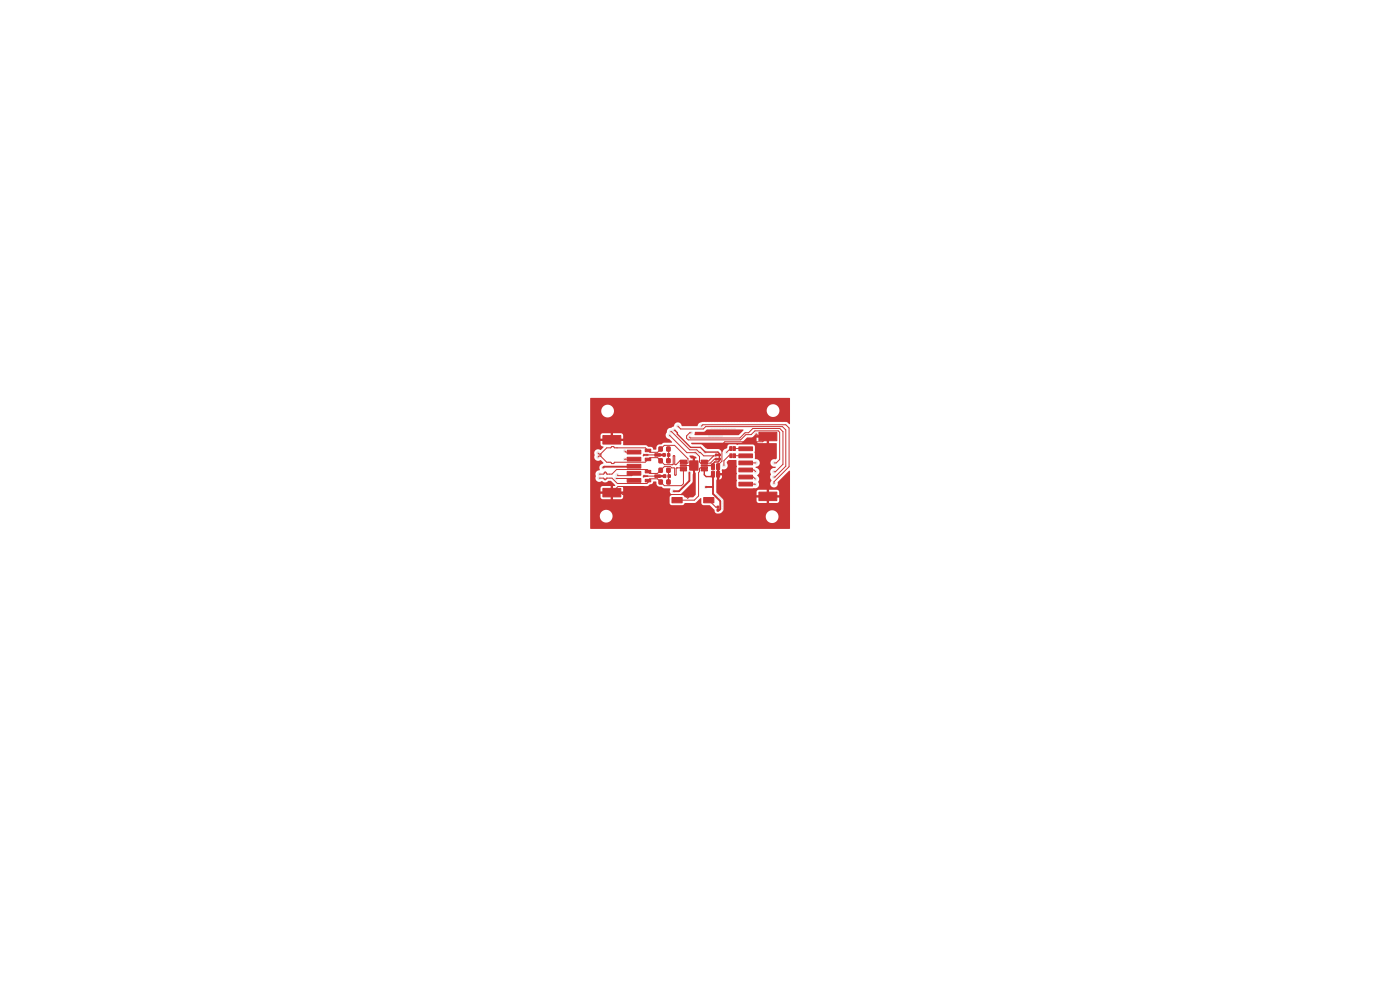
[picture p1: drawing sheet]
<svg xmlns="http://www.w3.org/2000/svg" width="297mm" height="210mm" viewBox="0 0 297 210" stroke-linecap="round" stroke-linejoin="round" font-family="sans-serif">
<g fill="#c83434" stroke="#c83434" stroke-width=".21">
<path d="M136.9 95.3h1.2v.5h-1.2z"/>
<path d="M136.9 97.2h1.2v.5h-1.2z"/>
<path d="M138.9 96.2h1.2v.6h-1.2z"/>
<path d="M155.5 96.3h.5v.8h-.5z"/>
<path d="M154.8 96.3h.5v.8h-.5z"/>
<path d="M139.8 97.3h.7v.9h-.7z"/>
<path d="M141.5 97.3h.6v.9h-.6z"/>
<path d="M141.7 100.7h.5v.6h-.5z"/>
<path d="M140.8 100.7h.4v.6h-.4z"/>
<path d="M139.8 94.8h.7v.9h-.7z"/>
<path d="M141.5 94.8h.6v.9h-.6z"/>
<path d="M152.4 97.2h.4v.4h-.4z"/>
<path d="M151.8 97.2h.4v.4h-.4z"/>
<path d="M151.8 96.3h.4v.4h-.4z"/>
<path d="M152.4 96.3h.4v.4h-.4z"/>
<path d="M149.3 105.5h2.1v1.2h-2.1z"/>
<path d="M142.6 105.5h2.1v1.2h-2.1z"/>
<path d="M144.3 97.6h1.4v.3h-1.4z"/>
<path d="M144.3 98.1h1.4v.3h-1.4z"/>
<path d="M144.3 98.6h1.4v.3h-1.4z"/>
<path d="M144.3 99.1h1.4v.3h-1.4z"/>
<path d="M144.3 99.6h1.4v.3h-1.4z"/>
<path d="M148.7 99.6h1.4v.3h-1.4z"/>
<path d="M148.7 99.1h1.4v.3h-1.4z"/>
<path d="M148.7 98.6h1.4v.3h-1.4z"/>
<path d="M148.7 98.1h1.4v.3h-1.4z"/>
<path d="M148.7 97.6h1.4v.3h-1.4z"/>
<path d="M146.3 97.8h1.8v1.9h-1.8z"/>
<path d="M152.1 107.4h.4v.4h-.4z"/>
<path d="M152.1 108h.4v.4h-.4z"/>
<path d="M136.9 99.8h1.2v.5h-1.2z"/>
<path d="M136.9 101.7h1.2v.5h-1.2z"/>
<path d="M138.9 100.7h1.2v.6h-1.2z"/>
<path d="M151 100l.6 .1-.1 1.1-.6-.1z"/>
<path d="M152.1 100l.6 .1-.1 1.1-.6-.1z"/>
<path d="M156.8 102.3h2.8v.8h-2.8z"/>
<path d="M156.8 100.8h2.8v.8h-2.8z"/>
<path d="M156.8 99.3h2.8v.8h-2.8z"/>
<path d="M156.8 97.8h2.8v.8h-2.8z"/>
<path d="M156.8 96.3h2.8v.8h-2.8z"/>
<path d="M156.8 94.8h2.8v.8h-2.8z"/>
<path d="M161 104.4h3.8v1.8h-3.8z"/>
<path d="M161 91.7h3.8v1.8h-3.8z"/>
<path d="M141.5 101.8h.7v.9h-.7z"/>
<path d="M139.8 101.8h.7v.9h-.7z"/>
<path d="M139.8 99.3h.7v.9h-.7z"/>
<path d="M141.5 99.3h.7v.9h-.7z"/>
<path d="M141.6 96.2h.5v.6h-.5z"/>
<path d="M140.7 96.2h.4v.6h-.4z"/>
<path d="M151 98.4l.6 .1-.1 1.1-.6-.1z"/>
<path d="M152.1 98.4l.6 .1-.1 1.1-.6-.1z"/>
<path d="M155.5 94.7h.5v.8h-.5z"/>
<path d="M154.8 94.7h.5v.8h-.5z"/>
<path d="M133.1 95.5h2.8v.8h-2.8z"/>
<path d="M133.1 97h2.8v.8h-2.8z"/>
<path d="M133.1 98.5h2.8v.8h-2.8z"/>
<path d="M133.1 100h2.8v.8h-2.8z"/>
<path d="M133.1 101.5h2.8v.8h-2.8z"/>
<path d="M127.9 92.4h3.8v1.8h-3.8z"/>
<path d="M127.9 103.6h3.8v1.8h-3.8z"/>
</g>
<g fill="#ececec" stroke="#ececec" stroke-width=".21">
<circle cx="143" cy="91.3" r=".3"/>
<circle cx="149.6" cy="95.9" r=".3"/>
<circle cx="137.2" cy="85" r=".3"/>
<circle cx="152.3" cy="103.2" r=".3"/>
<circle cx="139.2" cy="106.2" r=".3"/>
<circle cx="132" cy="109.2" r=".3"/>
<circle cx="141.4" cy="88.6" r=".3"/>
<circle cx="138.4" cy="86.2" r=".3"/>
<circle cx="151.6" cy="91.2" r=".3"/>
<circle cx="154.6" cy="87.4" r=".3"/>
<circle cx="159" cy="111.6" r=".3"/>
<circle cx="161.4" cy="108" r=".3"/>
<circle cx="160" cy="89.2" r=".3"/>
<circle cx="159.4" cy="89.2" r=".3"/>
<circle cx="127" cy="90.4" r=".3"/>
<circle cx="143.8" cy="86.2" r=".3"/>
<circle cx="138.6" cy="108" r=".3"/>
<circle cx="148.8" cy="110.4" r=".3"/>
<circle cx="137.2" cy="86.8" r=".3"/>
<circle cx="138.4" cy="88" r=".3"/>
<circle cx="126.4" cy="85" r=".3"/>
<circle cx="149.8" cy="85.6" r=".3"/>
<circle cx="139.8" cy="105.6" r=".3"/>
<circle cx="154.7" cy="103.2" r=".3"/>
<circle cx="134.4" cy="109.2" r=".3"/>
<circle cx="140.8" cy="89.2" r=".3"/>
<circle cx="155.8" cy="85" r=".3"/>
<circle cx="154.6" cy="89.2" r=".3"/>
<circle cx="151" cy="86.8" r=".3"/>
<circle cx="149.8" cy="88.6" r=".3"/>
<circle cx="139" cy="85" r=".3"/>
<circle cx="136.2" cy="110.4" r=".3"/>
<circle cx="161.2" cy="85" r=".3"/>
<circle cx="143.2" cy="86.2" r=".3"/>
<circle cx="129.6" cy="106.8" r=".3"/>
<circle cx="151.6" cy="88" r=".3"/>
<circle cx="141.6" cy="107.4" r=".3"/>
<circle cx="144.4" cy="88.6" r=".3"/>
<circle cx="133.8" cy="106.8" r=".3"/>
<circle cx="133.2" cy="109.8" r=".3"/>
<circle cx="127.6" cy="90.4" r=".3"/>
<circle cx="136.8" cy="111" r=".3"/>
<circle cx="140.2" cy="89.2" r=".3"/>
<circle cx="131.8" cy="86.2" r=".3"/>
<circle cx="134.8" cy="85" r=".3"/>
<circle cx="135" cy="107.4" r=".3"/>
<circle cx="159.6" cy="107.4" r=".3"/>
<circle cx="151" cy="87.4" r=".3"/>
<circle cx="135.4" cy="85" r=".3"/>
<circle cx="132.4" cy="88.6" r=".3"/>
<circle cx="156.4" cy="85" r=".3"/>
<circle cx="125.8" cy="85.6" r=".3"/>
<circle cx="136" cy="86.2" r=".3"/>
<circle cx="146.8" cy="85.6" r=".3"/>
<circle cx="166.7" cy="85" r=".3"/>
<circle cx="154" cy="85.6" r=".3"/>
<circle cx="156.4" cy="85.6" r=".3"/>
<circle cx="141.4" cy="86.8" r=".3"/>
<circle cx="134.8" cy="89.2" r=".3"/>
<circle cx="136" cy="88.6" r=".3"/>
<circle cx="156.4" cy="88" r=".3"/>
<circle cx="152.8" cy="91.2" r=".3"/>
<circle cx="145.8" cy="111" r=".3"/>
<circle cx="138.4" cy="89.2" r=".3"/>
<circle cx="152.4" cy="111" r=".3"/>
<circle cx="160.6" cy="86.8" r=".3"/>
<circle cx="149.2" cy="88.6" r=".3"/>
<circle cx="152.8" cy="87.4" r=".3"/>
<circle cx="137.8" cy="89.2" r=".3"/>
<circle cx="136.8" cy="109.8" r=".3"/>
<circle cx="146.4" cy="109.8" r=".3"/>
<circle cx="154.2" cy="111" r=".3"/>
<circle cx="155.4" cy="106.8" r=".3"/>
<circle cx="157" cy="86.2" r=".3"/>
<circle cx="149.2" cy="88" r=".3"/>
<circle cx="131.8" cy="86.8" r=".3"/>
<circle cx="153.5" cy="104.4" r=".3"/>
<circle cx="159" cy="110.4" r=".3"/>
<circle cx="145.6" cy="86.2" r=".3"/>
<circle cx="132.4" cy="85" r=".3"/>
<circle cx="132" cy="108" r=".3"/>
<circle cx="153.6" cy="106.2" r=".3"/>
<circle cx="136.8" cy="108.6" r=".3"/>
<circle cx="151.8" cy="109.2" r=".3"/>
<circle cx="151.6" cy="85" r=".3"/>
<circle cx="138" cy="107.4" r=".3"/>
<circle cx="137.4" cy="109.2" r=".3"/>
<circle cx="138" cy="108" r=".3"/>
<circle cx="158.2" cy="86.2" r=".3"/>
<circle cx="143.2" cy="89.2" r=".3"/>
<circle cx="154.8" cy="111.6" r=".3"/>
<circle cx="158.4" cy="108.6" r=".3"/>
<circle cx="149.8" cy="85" r=".3"/>
<circle cx="155.8" cy="91.2" r=".3"/>
<circle cx="154.8" cy="109.8" r=".3"/>
<circle cx="157.6" cy="89.2" r=".3"/>
<circle cx="133.6" cy="88.6" r=".3"/>
<circle cx="153.5" cy="102.6" r=".3"/>
<circle cx="156.6" cy="109.2" r=".3"/>
<circle cx="139.2" cy="106.8" r=".3"/>
<circle cx="133" cy="90.4" r=".3"/>
<circle cx="155.3" cy="104.4" r=".3"/>
<circle cx="151.2" cy="111" r=".3"/>
<circle cx="160.2" cy="109.2" r=".3"/>
<circle cx="125.8" cy="88" r=".3"/>
<circle cx="136" cy="89.8" r=".3"/>
<circle cx="137.4" cy="107.4" r=".3"/>
<circle cx="158.2" cy="86.8" r=".3"/>
<circle cx="150.4" cy="86.2" r=".3"/>
<circle cx="142.8" cy="109.2" r=".3"/>
<circle cx="137.8" cy="87.4" r=".3"/>
<circle cx="136" cy="87.4" r=".3"/>
<circle cx="160" cy="87.4" r=".3"/>
<circle cx="159.4" cy="85.6" r=".3"/>
<circle cx="152.9" cy="102.6" r=".3"/>
<circle cx="142" cy="87.4" r=".3"/>
<circle cx="142.6" cy="88" r=".3"/>
<circle cx="155.2" cy="91.2" r=".3"/>
<circle cx="160.2" cy="111.6" r=".3"/>
<circle cx="160.4" cy="92" r=".3"/>
<circle cx="143.2" cy="88.6" r=".3"/>
<circle cx="135.4" cy="90.4" r=".3"/>
<circle cx="152.2" cy="89.2" r=".3"/>
<circle cx="166.7" cy="88.6" r=".3"/>
<circle cx="159" cy="109.2" r=".3"/>
<circle cx="139" cy="87.4" r=".3"/>
<circle cx="147.6" cy="111" r=".3"/>
<circle cx="135" cy="109.2" r=".3"/>
<circle cx="145.6" cy="87.4" r=".3"/>
<circle cx="150.4" cy="87.4" r=".3"/>
<circle cx="165.8" cy="107.4" r=".3"/>
<circle cx="154" cy="86.2" r=".3"/>
<circle cx="157" cy="85" r=".3"/>
<circle cx="157.2" cy="109.8" r=".3"/>
<circle cx="143.2" cy="87.4" r=".3"/>
<circle cx="140.2" cy="88.6" r=".3"/>
<circle cx="152.9" cy="103.2" r=".3"/>
<circle cx="159.6" cy="110.4" r=".3"/>
<circle cx="166.7" cy="86.2" r=".3"/>
<circle cx="154" cy="85" r=".3"/>
<circle cx="143.2" cy="85" r=".3"/>
<circle cx="151.6" cy="89.2" r=".3"/>
<circle cx="139.8" cy="109.2" r=".3"/>
<circle cx="148.8" cy="111.6" r=".3"/>
<circle cx="157" cy="88" r=".3"/>
<circle cx="133.2" cy="111" r=".3"/>
<circle cx="156" cy="109.2" r=".3"/>
<circle cx="137.4" cy="106.2" r=".3"/>
<circle cx="160.6" cy="88.6" r=".3"/>
<circle cx="125.8" cy="89.2" r=".3"/>
<circle cx="145.8" cy="110.4" r=".3"/>
<circle cx="154.8" cy="108.6" r=".3"/>
<circle cx="151.8" cy="111.6" r=".3"/>
<circle cx="136" cy="85" r=".3"/>
<circle cx="134.2" cy="85" r=".3"/>
<circle cx="158.8" cy="85.6" r=".3"/>
<circle cx="155.1" cy="101.2" r=".3"/>
<circle cx="157.8" cy="108" r=".3"/>
<circle cx="138.4" cy="85" r=".3"/>
<circle cx="137.8" cy="86.2" r=".3"/>
<circle cx="132" cy="108.6" r=".3"/>
<circle cx="152.9" cy="105" r=".3"/>
<circle cx="143.4" cy="110.4" r=".3"/>
<circle cx="153.6" cy="109.2" r=".3"/>
<circle cx="154" cy="88" r=".3"/>
<circle cx="167" cy="108" r=".3"/>
<circle cx="150.4" cy="88" r=".3"/>
<circle cx="153.6" cy="106.8" r=".3"/>
<circle cx="139.6" cy="85.6" r=".3"/>
<circle cx="132" cy="111" r=".3"/>
<circle cx="142.6" cy="88.6" r=".3"/>
<circle cx="145.6" cy="85" r=".3"/>
<circle cx="136.6" cy="85.6" r=".3"/>
<circle cx="148" cy="87.4" r=".3"/>
<circle cx="155.2" cy="85.6" r=".3"/>
<circle cx="133" cy="85" r=".3"/>
<circle cx="146.2" cy="85.6" r=".3"/>
<circle cx="126.4" cy="90.4" r=".3"/>
<circle cx="141.4" cy="85.6" r=".3"/>
<circle cx="166.1" cy="85" r=".3"/>
<circle cx="160" cy="88.6" r=".3"/>
<circle cx="161.8" cy="85" r=".3"/>
<circle cx="137.8" cy="88.6" r=".3"/>
<circle cx="135.6" cy="111.6" r=".3"/>
<circle cx="126" cy="106.8" r=".3"/>
<circle cx="152.8" cy="85.6" r=".3"/>
<circle cx="145" cy="86.2" r=".3"/>
<circle cx="155.4" cy="111" r=".3"/>
<circle cx="156" cy="107.4" r=".3"/>
<circle cx="145" cy="88" r=".3"/>
<circle cx="132" cy="106.8" r=".3"/>
<circle cx="141.6" cy="111.6" r=".3"/>
<circle cx="152.2" cy="87.4" r=".3"/>
<circle cx="153.5" cy="105.6" r=".3"/>
<circle cx="137.4" cy="111" r=".3"/>
<circle cx="144.4" cy="88" r=".3"/>
<circle cx="138" cy="111.6" r=".3"/>
<circle cx="154.2" cy="106.8" r=".3"/>
<circle cx="142.8" cy="110.4" r=".3"/>
<circle cx="145" cy="87.4" r=".3"/>
<circle cx="142.6" cy="85" r=".3"/>
<circle cx="160.8" cy="109.2" r=".3"/>
<circle cx="157" cy="86.8" r=".3"/>
<circle cx="144.6" cy="111" r=".3"/>
<circle cx="138.4" cy="85.6" r=".3"/>
<circle cx="140.4" cy="109.2" r=".3"/>
<circle cx="139" cy="88" r=".3"/>
<circle cx="136.6" cy="85" r=".3"/>
<circle cx="149.2" cy="86.8" r=".3"/>
<circle cx="159" cy="109.8" r=".3"/>
<circle cx="155.4" cy="110.4" r=".3"/>
<circle cx="132.4" cy="86.8" r=".3"/>
<circle cx="141" cy="109.2" r=".3"/>
<circle cx="157.6" cy="85.6" r=".3"/>
<circle cx="159.6" cy="108" r=".3"/>
<circle cx="131.8" cy="88" r=".3"/>
<circle cx="132.6" cy="109.2" r=".3"/>
<circle cx="157.8" cy="109.8" r=".3"/>
<circle cx="143.8" cy="88.6" r=".3"/>
<circle cx="130.8" cy="106.8" r=".3"/>
<circle cx="156.6" cy="109.8" r=".3"/>
<circle cx="143.4" cy="109.8" r=".3"/>
<circle cx="136.6" cy="89.2" r=".3"/>
<circle cx="131.8" cy="85.6" r=".3"/>
<circle cx="138.6" cy="107.4" r=".3"/>
<circle cx="139.6" cy="86.8" r=".3"/>
<circle cx="148.2" cy="111" r=".3"/>
<circle cx="141.6" cy="106.2" r=".3"/>
<circle cx="153" cy="111.6" r=".3"/>
<circle cx="136" cy="88" r=".3"/>
<circle cx="132.4" cy="87.4" r=".3"/>
<circle cx="130.6" cy="89.8" r=".3"/>
<circle cx="147" cy="109.8" r=".3"/>
<circle cx="152.4" cy="110.4" r=".3"/>
<circle cx="136.8" cy="107.4" r=".3"/>
<circle cx="158.4" cy="109.2" r=".3"/>
<circle cx="154.2" cy="108" r=".3"/>
<circle cx="127" cy="85" r=".3"/>
<circle cx="153" cy="109.8" r=".3"/>
<circle cx="157.2" cy="110.4" r=".3"/>
<circle cx="159" cy="108.6" r=".3"/>
<circle cx="137.2" cy="96.5" r=".3"/>
<circle cx="154" cy="89.2" r=".3"/>
<circle cx="127.6" cy="91" r=".3"/>
<circle cx="139" cy="88.6" r=".3"/>
<circle cx="132.6" cy="108.6" r=".3"/>
<circle cx="135.6" cy="107.4" r=".3"/>
<circle cx="150.6" cy="110.4" r=".3"/>
<circle cx="144" cy="111" r=".3"/>
<circle cx="136.8" cy="106.2" r=".3"/>
<circle cx="166.4" cy="111.6" r=".3"/>
<circle cx="160.6" cy="86.2" r=".3"/>
<circle cx="156.4" cy="88.6" r=".3"/>
<circle cx="148.6" cy="89.2" r=".3"/>
<circle cx="125.8" cy="87.4" r=".3"/>
<circle cx="146.8" cy="88" r=".3"/>
<circle cx="154.8" cy="106.2" r=".3"/>
<circle cx="150.6" cy="109.8" r=".3"/>
<circle cx="158.8" cy="89.2" r=".3"/>
<circle cx="152.8" cy="88" r=".3"/>
<circle cx="135.4" cy="89.2" r=".3"/>
<circle cx="131.2" cy="85" r=".3"/>
<circle cx="157.2" cy="108.6" r=".3"/>
<circle cx="136.2" cy="106.8" r=".3"/>
<circle cx="157.6" cy="85" r=".3"/>
<circle cx="155.2" cy="87.4" r=".3"/>
<circle cx="159.4" cy="86.8" r=".3"/>
<circle cx="156" cy="109.8" r=".3"/>
<circle cx="155.3" cy="105.6" r=".3"/>
<circle cx="153.6" cy="110.4" r=".3"/>
<circle cx="155.7" cy="101.2" r=".3"/>
<circle cx="154.7" cy="105" r=".3"/>
<circle cx="126" cy="111" r=".3"/>
<circle cx="148.6" cy="86.2" r=".3"/>
<circle cx="167" cy="111.6" r=".3"/>
<circle cx="131.2" cy="90.4" r=".3"/>
<circle cx="145.2" cy="109.8" r=".3"/>
<circle cx="138.6" cy="109.2" r=".3"/>
<circle cx="137.2" cy="89.2" r=".3"/>
<circle cx="150.6" cy="111" r=".3"/>
<circle cx="136.2" cy="109.8" r=".3"/>
<circle cx="157.6" cy="88.6" r=".3"/>
<circle cx="128.2" cy="91" r=".3"/>
<circle cx="166.4" cy="108" r=".3"/>
<circle cx="151.2" cy="110.4" r=".3"/>
<circle cx="138.6" cy="111" r=".3"/>
<circle cx="135" cy="108" r=".3"/>
<circle cx="136.8" cy="106.8" r=".3"/>
<circle cx="155.4" cy="108.6" r=".3"/>
<circle cx="151.6" cy="85.6" r=".3"/>
<circle cx="130.2" cy="106.8" r=".3"/>
<circle cx="136.6" cy="88.6" r=".3"/>
<circle cx="132.4" cy="86.2" r=".3"/>
<circle cx="158.8" cy="86.2" r=".3"/>
<circle cx="146.2" cy="86.2" r=".3"/>
<circle cx="134.8" cy="89.8" r=".3"/>
<circle cx="156.4" cy="86.2" r=".3"/>
<circle cx="157" cy="89.2" r=".3"/>
<circle cx="156.6" cy="108.6" r=".3"/>
<circle cx="153.6" cy="109.8" r=".3"/>
<circle cx="144.4" cy="89.2" r=".3"/>
<circle cx="157.2" cy="111" r=".3"/>
<circle cx="159.6" cy="111" r=".3"/>
<circle cx="145" cy="85" r=".3"/>
<circle cx="148.2" cy="109.8" r=".3"/>
<circle cx="137.2" cy="86.2" r=".3"/>
<circle cx="149.8" cy="86.8" r=".3"/>
<circle cx="129.4" cy="90.4" r=".3"/>
<circle cx="157.8" cy="109.2" r=".3"/>
<circle cx="166.4" cy="107.4" r=".3"/>
<circle cx="139.8" cy="111" r=".3"/>
<circle cx="158.4" cy="111.6" r=".3"/>
<circle cx="160" cy="86.2" r=".3"/>
<circle cx="136.7" cy="101" r=".3"/>
<circle cx="132.4" cy="88" r=".3"/>
<circle cx="131.8" cy="89.2" r=".3"/>
<circle cx="133.6" cy="85" r=".3"/>
<circle cx="145" cy="86.8" r=".3"/>
<circle cx="139.2" cy="110.4" r=".3"/>
<circle cx="152.8" cy="86.2" r=".3"/>
<circle cx="154.2" cy="106.2" r=".3"/>
<circle cx="131.4" cy="108.6" r=".3"/>
<circle cx="126.6" cy="111.6" r=".3"/>
<circle cx="155.2" cy="88" r=".3"/>
<circle cx="152.4" cy="109.8" r=".3"/>
<circle cx="155.8" cy="86.8" r=".3"/>
<circle cx="134.2" cy="85.6" r=".3"/>
<circle cx="133.8" cy="107.4" r=".3"/>
<circle cx="167" cy="109.8" r=".3"/>
<circle cx="151" cy="85.6" r=".3"/>
<circle cx="131.4" cy="111" r=".3"/>
<circle cx="128.2" cy="90.4" r=".3"/>
<circle cx="131.2" cy="91" r=".3"/>
<circle cx="133.2" cy="111.6" r=".3"/>
<circle cx="138.6" cy="111.6" r=".3"/>
<circle cx="131.4" cy="107.4" r=".3"/>
<circle cx="151.6" cy="86.8" r=".3"/>
<circle cx="143.4" cy="109.2" r=".3"/>
<circle cx="134.4" cy="107.4" r=".3"/>
<circle cx="146.8" cy="86.2" r=".3"/>
<circle cx="141.4" cy="87.4" r=".3"/>
<circle cx="154.1" cy="103.8" r=".3"/>
<circle cx="155.8" cy="86.2" r=".3"/>
<circle cx="154.1" cy="105" r=".3"/>
<circle cx="155.7" cy="98.2" r=".3"/>
<circle cx="142" cy="85.6" r=".3"/>
<circle cx="167" cy="111" r=".3"/>
<circle cx="133" cy="85.6" r=".3"/>
<circle cx="155.7" cy="100.6" r=".3"/>
<circle cx="156.4" cy="86.8" r=".3"/>
<circle cx="154.2" cy="110.4" r=".3"/>
<circle cx="134.8" cy="85.6" r=".3"/>
<circle cx="140.4" cy="105.6" r=".3"/>
<circle cx="161.2" cy="87.4" r=".3"/>
<circle cx="146.4" cy="111.6" r=".3"/>
<circle cx="137.8" cy="85" r=".3"/>
<circle cx="155.2" cy="85" r=".3"/>
<circle cx="136.6" cy="86.2" r=".3"/>
<circle cx="160.6" cy="88" r=".3"/>
<circle cx="130.6" cy="91" r=".3"/>
<circle cx="138" cy="111" r=".3"/>
<circle cx="127" cy="89.8" r=".3"/>
<circle cx="156" cy="108" r=".3"/>
<circle cx="138.4" cy="87.4" r=".3"/>
<circle cx="141" cy="107.4" r=".3"/>
<circle cx="128.8" cy="91" r=".3"/>
<circle cx="142.6" cy="86.8" r=".3"/>
<circle cx="149.4" cy="111.6" r=".3"/>
<circle cx="133.6" cy="86.8" r=".3"/>
<circle cx="139.2" cy="108.6" r=".3"/>
<circle cx="148.2" cy="110.4" r=".3"/>
<circle cx="157.6" cy="86.8" r=".3"/>
<circle cx="160.8" cy="109.8" r=".3"/>
<circle cx="145.8" cy="109.8" r=".3"/>
<circle cx="125.8" cy="86.2" r=".3"/>
<circle cx="160.8" cy="107.4" r=".3"/>
<circle cx="157.6" cy="88" r=".3"/>
<circle cx="146.2" cy="87.4" r=".3"/>
<circle cx="148.2" cy="109.2" r=".3"/>
<circle cx="133.6" cy="89.8" r=".3"/>
<circle cx="137.4" cy="109.8" r=".3"/>
<circle cx="139.2" cy="109.2" r=".3"/>
<circle cx="153.6" cy="108" r=".3"/>
<circle cx="151.2" cy="92.4" r=".3"/>
<circle cx="139" cy="89.2" r=".3"/>
<circle cx="133" cy="89.2" r=".3"/>
<circle cx="149.4" cy="109.8" r=".3"/>
<circle cx="154.8" cy="110.4" r=".3"/>
<circle cx="156" cy="111" r=".3"/>
<circle cx="141.6" cy="106.8" r=".3"/>
<circle cx="160.2" cy="107.4" r=".3"/>
<circle cx="131.8" cy="91" r=".3"/>
<circle cx="150.4" cy="85" r=".3"/>
<circle cx="151" cy="88.6" r=".3"/>
<circle cx="154.6" cy="88.6" r=".3"/>
<circle cx="140.4" cy="107.4" r=".3"/>
<circle cx="130.8" cy="107.4" r=".3"/>
<circle cx="149.2" cy="85" r=".3"/>
<circle cx="147" cy="109.2" r=".3"/>
<circle cx="145.2" cy="111.6" r=".3"/>
<circle cx="134.2" cy="90.4" r=".3"/>
<circle cx="141.4" cy="85" r=".3"/>
<circle cx="139.2" cy="105.6" r=".3"/>
<circle cx="135" cy="106.8" r=".3"/>
<circle cx="135" cy="108.6" r=".3"/>
<circle cx="134.2" cy="89.8" r=".3"/>
<circle cx="153.4" cy="89.2" r=".3"/>
<circle cx="157.8" cy="108.6" r=".3"/>
<circle cx="148.6" cy="88.6" r=".3"/>
<circle cx="143.8" cy="87.4" r=".3"/>
<circle cx="158.4" cy="110.4" r=".3"/>
<circle cx="133.2" cy="110.4" r=".3"/>
<circle cx="136.2" cy="107.4" r=".3"/>
<circle cx="155.7" cy="100" r=".3"/>
<circle cx="135.6" cy="111" r=".3"/>
<circle cx="161.2" cy="86.2" r=".3"/>
<circle cx="146.2" cy="89.2" r=".3"/>
<circle cx="151" cy="85" r=".3"/>
<circle cx="156" cy="111.6" r=".3"/>
<circle cx="136.6" cy="88" r=".3"/>
<circle cx="148.8" cy="109.8" r=".3"/>
<circle cx="150" cy="111" r=".3"/>
<circle cx="148.6" cy="85" r=".3"/>
<circle cx="158.2" cy="85.6" r=".3"/>
<circle cx="139.2" cy="111" r=".3"/>
<circle cx="140.8" cy="88" r=".3"/>
<circle cx="135.4" cy="85.6" r=".3"/>
<circle cx="145.6" cy="86.8" r=".3"/>
<circle cx="133" cy="89.8" r=".3"/>
<circle cx="125.8" cy="86.8" r=".3"/>
<circle cx="132" cy="107.4" r=".3"/>
<circle cx="159.4" cy="87.4" r=".3"/>
<circle cx="136.8" cy="108" r=".3"/>
<circle cx="152.3" cy="103.8" r=".3"/>
<circle cx="133.2" cy="106.8" r=".3"/>
<circle cx="140.4" cy="109.8" r=".3"/>
<circle cx="140.8" cy="85" r=".3"/>
<circle cx="139.2" cy="109.8" r=".3"/>
<circle cx="145.2" cy="111" r=".3"/>
<circle cx="144.6" cy="109.2" r=".3"/>
<circle cx="135.6" cy="106.8" r=".3"/>
<circle cx="147.4" cy="87.4" r=".3"/>
<circle cx="167" cy="110.4" r=".3"/>
<circle cx="145.8" cy="109.2" r=".3"/>
<circle cx="130.8" cy="111.6" r=".3"/>
<circle cx="158.2" cy="87.4" r=".3"/>
<circle cx="136.2" cy="111" r=".3"/>
<circle cx="152.2" cy="85" r=".3"/>
<circle cx="154.8" cy="107.4" r=".3"/>
<circle cx="142" cy="85" r=".3"/>
<circle cx="138.6" cy="106.2" r=".3"/>
<circle cx="136.8" cy="109.2" r=".3"/>
<circle cx="153.4" cy="86.2" r=".3"/>
<circle cx="139.6" cy="89.2" r=".3"/>
<circle cx="136.6" cy="87.4" r=".3"/>
<circle cx="158.8" cy="88" r=".3"/>
<circle cx="150" cy="109.8" r=".3"/>
<circle cx="165.8" cy="111.6" r=".3"/>
<circle cx="146.8" cy="85" r=".3"/>
<circle cx="134.2" cy="86.2" r=".3"/>
<circle cx="153.4" cy="91.2" r=".3"/>
<circle cx="130.6" cy="90.4" r=".3"/>
<circle cx="131.2" cy="89.8" r=".3"/>
<circle cx="133.6" cy="87.4" r=".3"/>
<circle cx="142.2" cy="110.4" r=".3"/>
<circle cx="155.8" cy="89.2" r=".3"/>
<circle cx="159.4" cy="88.6" r=".3"/>
<circle cx="141.6" cy="108.6" r=".3"/>
<circle cx="148" cy="85.6" r=".3"/>
<circle cx="135.6" cy="109.2" r=".3"/>
<circle cx="151.6" cy="86.2" r=".3"/>
<circle cx="138" cy="106.8" r=".3"/>
<circle cx="161.2" cy="85.6" r=".3"/>
<circle cx="143.8" cy="85" r=".3"/>
<circle cx="132.6" cy="109.8" r=".3"/>
<circle cx="139" cy="86.8" r=".3"/>
<circle cx="141" cy="111.6" r=".3"/>
<circle cx="127.2" cy="106.8" r=".3"/>
<circle cx="133.6" cy="88" r=".3"/>
<circle cx="157.2" cy="108" r=".3"/>
<circle cx="161.4" cy="111" r=".3"/>
<circle cx="126.4" cy="88.6" r=".3"/>
<circle cx="137.4" cy="106.8" r=".3"/>
<circle cx="161.8" cy="89.2" r=".3"/>
<circle cx="151.2" cy="111.6" r=".3"/>
<circle cx="150" cy="111.6" r=".3"/>
<circle cx="139.8" cy="108.6" r=".3"/>
<circle cx="150.4" cy="88.6" r=".3"/>
<circle cx="134.4" cy="111.6" r=".3"/>
<circle cx="149.8" cy="88" r=".3"/>
<circle cx="134.8" cy="86.8" r=".3"/>
<circle cx="146.2" cy="85" r=".3"/>
<circle cx="151" cy="89.2" r=".3"/>
<circle cx="161.2" cy="88" r=".3"/>
<circle cx="154.8" cy="109.2" r=".3"/>
<circle cx="155.3" cy="105" r=".3"/>
<circle cx="137.8" cy="88" r=".3"/>
<circle cx="134.2" cy="86.8" r=".3"/>
<circle cx="150.4" cy="86.8" r=".3"/>
<circle cx="142.8" cy="109.8" r=".3"/>
<circle cx="153.5" cy="103.8" r=".3"/>
<circle cx="154.5" cy="101.2" r=".3"/>
<circle cx="143.8" cy="86.8" r=".3"/>
<circle cx="132" cy="109.8" r=".3"/>
<circle cx="150.6" cy="109.2" r=".3"/>
<circle cx="136.2" cy="109.2" r=".3"/>
<circle cx="154.5" cy="100.6" r=".3"/>
<circle cx="142.6" cy="85.6" r=".3"/>
<circle cx="144" cy="110.4" r=".3"/>
<circle cx="134.8" cy="86.2" r=".3"/>
<circle cx="161.2" cy="86.8" r=".3"/>
<circle cx="131.4" cy="111.6" r=".3"/>
<circle cx="156.4" cy="87.4" r=".3"/>
<circle cx="160.6" cy="85" r=".3"/>
<circle cx="126.4" cy="89.2" r=".3"/>
<circle cx="160.6" cy="87.4" r=".3"/>
<circle cx="142.2" cy="109.8" r=".3"/>
<circle cx="153.4" cy="88.6" r=".3"/>
<circle cx="134.4" cy="111" r=".3"/>
<circle cx="126.4" cy="85.6" r=".3"/>
<circle cx="161.4" cy="107.4" r=".3"/>
<circle cx="147.4" cy="85" r=".3"/>
<circle cx="133.2" cy="107.4" r=".3"/>
<circle cx="156" cy="108.6" r=".3"/>
<circle cx="133.6" cy="85.6" r=".3"/>
<circle cx="151" cy="86.2" r=".3"/>
<circle cx="144.4" cy="85" r=".3"/>
<circle cx="159" cy="111" r=".3"/>
<circle cx="134.8" cy="90.4" r=".3"/>
<circle cx="153.4" cy="85" r=".3"/>
<circle cx="159.4" cy="85" r=".3"/>
<circle cx="155.4" cy="108" r=".3"/>
<circle cx="137.2" cy="88" r=".3"/>
<circle cx="152.2" cy="85.6" r=".3"/>
<circle cx="136" cy="89.2" r=".3"/>
<circle cx="132" cy="110.4" r=".3"/>
<circle cx="136" cy="86.8" r=".3"/>
<circle cx="153.4" cy="86.8" r=".3"/>
<circle cx="141.6" cy="109.8" r=".3"/>
<circle cx="153" cy="92.4" r=".3"/>
<circle cx="135" cy="110.4" r=".3"/>
<circle cx="139.6" cy="88" r=".3"/>
<circle cx="133" cy="91" r=".3"/>
<circle cx="148" cy="86.8" r=".3"/>
<circle cx="133.8" cy="109.2" r=".3"/>
<circle cx="146.4" cy="111" r=".3"/>
<circle cx="135.4" cy="86.8" r=".3"/>
<circle cx="141" cy="105.6" r=".3"/>
<circle cx="155.1" cy="98.2" r=".3"/>
<circle cx="142" cy="88" r=".3"/>
<circle cx="145.6" cy="88.6" r=".3"/>
<circle cx="153.5" cy="105" r=".3"/>
<circle cx="139.2" cy="111.6" r=".3"/>
<circle cx="166.4" cy="108.6" r=".3"/>
<circle cx="152.9" cy="105.6" r=".3"/>
<circle cx="154.1" cy="105.6" r=".3"/>
<circle cx="156.6" cy="111.6" r=".3"/>
<circle cx="154.8" cy="106.8" r=".3"/>
<circle cx="132.4" cy="89.8" r=".3"/>
<circle cx="126.6" cy="107.4" r=".3"/>
<circle cx="131.8" cy="87.4" r=".3"/>
<circle cx="132.6" cy="108" r=".3"/>
<circle cx="126.4" cy="89.8" r=".3"/>
<circle cx="161.4" cy="111.6" r=".3"/>
<circle cx="133.6" cy="90.4" r=".3"/>
<circle cx="155.8" cy="87.4" r=".3"/>
<circle cx="138.6" cy="110.4" r=".3"/>
<circle cx="144" cy="109.2" r=".3"/>
<circle cx="130" cy="91" r=".3"/>
<circle cx="146.8" cy="88.6" r=".3"/>
<circle cx="137.4" cy="108.6" r=".3"/>
<circle cx="126.4" cy="91" r=".3"/>
<circle cx="150.4" cy="85.6" r=".3"/>
<circle cx="156.6" cy="110.4" r=".3"/>
<circle cx="160.2" cy="110.4" r=".3"/>
<circle cx="154.2" cy="108.6" r=".3"/>
<circle cx="139" cy="86.2" r=".3"/>
<circle cx="158.2" cy="88" r=".3"/>
<circle cx="141" cy="111" r=".3"/>
<circle cx="144.4" cy="86.2" r=".3"/>
<circle cx="141.4" cy="86.2" r=".3"/>
<circle cx="150.6" cy="92.4" r=".3"/>
<circle cx="160" cy="85" r=".3"/>
<circle cx="154.7" cy="104.4" r=".3"/>
<circle cx="134.4" cy="108.6" r=".3"/>
<circle cx="155.1" cy="100" r=".3"/>
<circle cx="146.4" cy="110.4" r=".3"/>
<circle cx="131.4" cy="109.8" r=".3"/>
<circle cx="160.8" cy="111" r=".3"/>
<circle cx="133" cy="88" r=".3"/>
<circle cx="161.2" cy="88.6" r=".3"/>
<circle cx="131.8" cy="89.8" r=".3"/>
<circle cx="158.8" cy="87.4" r=".3"/>
<circle cx="140.8" cy="85.6" r=".3"/>
<circle cx="148.6" cy="88" r=".3"/>
<circle cx="159.4" cy="88" r=".3"/>
<circle cx="143.4" cy="111.6" r=".3"/>
<circle cx="139.8" cy="106.2" r=".3"/>
<circle cx="148" cy="86.2" r=".3"/>
<circle cx="156.6" cy="111" r=".3"/>
<circle cx="134.2" cy="87.4" r=".3"/>
<circle cx="146.4" cy="109.2" r=".3"/>
<circle cx="155.8" cy="85.6" r=".3"/>
<circle cx="142.6" cy="89.2" r=".3"/>
<circle cx="152.8" cy="86.8" r=".3"/>
<circle cx="166" cy="89.2" r=".3"/>
<circle cx="127.6" cy="89.8" r=".3"/>
<circle cx="131.4" cy="108" r=".3"/>
<circle cx="147.4" cy="86.2" r=".3"/>
<circle cx="146.8" cy="89.2" r=".3"/>
<circle cx="157" cy="88.6" r=".3"/>
<circle cx="154.2" cy="109.8" r=".3"/>
<circle cx="157.2" cy="109.2" r=".3"/>
<circle cx="139.2" cy="107.4" r=".3"/>
<circle cx="141.6" cy="111" r=".3"/>
<circle cx="133.6" cy="86.2" r=".3"/>
<circle cx="155.2" cy="86.2" r=".3"/>
<circle cx="132.6" cy="107.4" r=".3"/>
<circle cx="140.4" cy="108.6" r=".3"/>
<circle cx="138" cy="109.2" r=".3"/>
<circle cx="160.6" cy="89.2" r=".3"/>
<circle cx="125.8" cy="88.6" r=".3"/>
<circle cx="152.2" cy="88.6" r=".3"/>
<circle cx="154.2" cy="107.4" r=".3"/>
<circle cx="149.8" cy="86.2" r=".3"/>
<circle cx="145.6" cy="89.2" r=".3"/>
<circle cx="141" cy="106.8" r=".3"/>
<circle cx="134.4" cy="106.8" r=".3"/>
<circle cx="155.1" cy="100.6" r=".3"/>
<circle cx="144.4" cy="85.6" r=".3"/>
<circle cx="155.4" cy="106.2" r=".3"/>
<circle cx="153.5" cy="103.2" r=".3"/>
<circle cx="154" cy="88.6" r=".3"/>
<circle cx="154.8" cy="108" r=".3"/>
<circle cx="151" cy="91.2" r=".3"/>
<circle cx="158.8" cy="85" r=".3"/>
<circle cx="148" cy="89.2" r=".3"/>
<circle cx="158.2" cy="89.2" r=".3"/>
<circle cx="150" cy="109.2" r=".3"/>
<circle cx="148.8" cy="111" r=".3"/>
<circle cx="141.4" cy="88" r=".3"/>
<circle cx="145.8" cy="111.6" r=".3"/>
<circle cx="157.8" cy="110.4" r=".3"/>
<circle cx="147.4" cy="88" r=".3"/>
<circle cx="153.6" cy="111.6" r=".3"/>
<circle cx="155.7" cy="98.8" r=".3"/>
<circle cx="154" cy="86.8" r=".3"/>
<circle cx="154.1" cy="102.6" r=".3"/>
<circle cx="140.4" cy="111" r=".3"/>
<circle cx="142.2" cy="111.6" r=".3"/>
<circle cx="154.6" cy="85" r=".3"/>
<circle cx="151.6" cy="88.6" r=".3"/>
<circle cx="142" cy="86.8" r=".3"/>
<circle cx="154.7" cy="105.6" r=".3"/>
<circle cx="133" cy="88.6" r=".3"/>
<circle cx="137.2" cy="85.6" r=".3"/>
<circle cx="132.4" cy="91" r=".3"/>
<circle cx="128.8" cy="90.4" r=".3"/>
<circle cx="147" cy="110.4" r=".3"/>
<circle cx="147.6" cy="110.4" r=".3"/>
<circle cx="132.4" cy="90.4" r=".3"/>
<circle cx="155.4" cy="111.6" r=".3"/>
<circle cx="148" cy="85" r=".3"/>
<circle cx="166.7" cy="89.2" r=".3"/>
<circle cx="153.4" cy="88" r=".3"/>
<circle cx="152.2" cy="91.2" r=".3"/>
<circle cx="140.2" cy="87.4" r=".3"/>
<circle cx="139.8" cy="109.8" r=".3"/>
<circle cx="139.6" cy="85" r=".3"/>
<circle cx="152.4" cy="92.4" r=".3"/>
<circle cx="125.8" cy="89.8" r=".3"/>
<circle cx="146.2" cy="88" r=".3"/>
<circle cx="136.2" cy="108" r=".3"/>
<circle cx="125.8" cy="85" r=".3"/>
<circle cx="133.2" cy="108" r=".3"/>
<circle cx="141" cy="106.2" r=".3"/>
<circle cx="138" cy="109.8" r=".3"/>
<circle cx="155.3" cy="103.8" r=".3"/>
<circle cx="142.2" cy="109.2" r=".3"/>
<circle cx="133.8" cy="110.4" r=".3"/>
<circle cx="155.8" cy="88.6" r=".3"/>
<circle cx="152.2" cy="86.2" r=".3"/>
<circle cx="126" cy="107.4" r=".3"/>
<circle cx="140.2" cy="86.8" r=".3"/>
<circle cx="148" cy="88" r=".3"/>
<circle cx="140.8" cy="86.2" r=".3"/>
<circle cx="127" cy="91" r=".3"/>
<circle cx="154.6" cy="86.8" r=".3"/>
<circle cx="141" cy="110.4" r=".3"/>
<circle cx="131.4" cy="109.2" r=".3"/>
<circle cx="151.8" cy="111" r=".3"/>
<circle cx="143.4" cy="111" r=".3"/>
<circle cx="152.4" cy="109.2" r=".3"/>
<circle cx="140.4" cy="106.2" r=".3"/>
<circle cx="154.7" cy="103.8" r=".3"/>
<circle cx="132.4" cy="89.2" r=".3"/>
<circle cx="134.4" cy="109.8" r=".3"/>
<circle cx="131.8" cy="90.4" r=".3"/>
<circle cx="157.8" cy="111" r=".3"/>
<circle cx="142.6" cy="86.2" r=".3"/>
<circle cx="150.6" cy="111.6" r=".3"/>
<circle cx="140.2" cy="85.6" r=".3"/>
<circle cx="141.6" cy="105.6" r=".3"/>
<circle cx="142.6" cy="87.4" r=".3"/>
<circle cx="157.8" cy="111.6" r=".3"/>
<circle cx="167" cy="109.2" r=".3"/>
<circle cx="155.2" cy="88.6" r=".3"/>
<circle cx="152.8" cy="89.2" r=".3"/>
<circle cx="148.6" cy="85.6" r=".3"/>
<circle cx="152.9" cy="104.4" r=".3"/>
<circle cx="134.2" cy="88" r=".3"/>
<circle cx="139.6" cy="86.2" r=".3"/>
<circle cx="134.4" cy="110.4" r=".3"/>
<circle cx="146.8" cy="87.4" r=".3"/>
<circle cx="137.2" cy="87.4" r=".3"/>
<circle cx="137.7" cy="104.4" r=".3"/>
<circle cx="153" cy="110.4" r=".3"/>
<circle cx="145" cy="88.6" r=".3"/>
<circle cx="160.8" cy="111.6" r=".3"/>
<circle cx="140.8" cy="86.8" r=".3"/>
<circle cx="156" cy="110.4" r=".3"/>
<circle cx="139.6" cy="87.4" r=".3"/>
<circle cx="157" cy="87.4" r=".3"/>
<circle cx="149.4" cy="110.4" r=".3"/>
<circle cx="160.8" cy="108" r=".3"/>
<circle cx="132" cy="111.6" r=".3"/>
<circle cx="142.2" cy="111" r=".3"/>
<circle cx="133.8" cy="109.8" r=".3"/>
<circle cx="133.8" cy="108.6" r=".3"/>
<circle cx="151" cy="88" r=".3"/>
<circle cx="158.4" cy="109.8" r=".3"/>
<circle cx="160.8" cy="110.4" r=".3"/>
<circle cx="153.4" cy="87.4" r=".3"/>
<circle cx="151.2" cy="109.8" r=".3"/>
<circle cx="155.4" cy="109.8" r=".3"/>
<circle cx="151.2" cy="109.2" r=".3"/>
<circle cx="155.7" cy="99.4" r=".3"/>
<circle cx="136.6" cy="86.8" r=".3"/>
<circle cx="167" cy="108.6" r=".3"/>
<circle cx="135" cy="109.8" r=".3"/>
<circle cx="152.8" cy="85" r=".3"/>
<circle cx="159.6" cy="109.2" r=".3"/>
<circle cx="147.6" cy="109.8" r=".3"/>
<circle cx="141.4" cy="89.2" r=".3"/>
<circle cx="138.6" cy="108.6" r=".3"/>
<circle cx="135" cy="111.6" r=".3"/>
<circle cx="143.2" cy="88" r=".3"/>
<circle cx="144" cy="109.8" r=".3"/>
<circle cx="147.4" cy="86.8" r=".3"/>
<circle cx="133.2" cy="108.6" r=".3"/>
<circle cx="153.6" cy="111" r=".3"/>
<circle cx="140.2" cy="85" r=".3"/>
<circle cx="135.6" cy="109.8" r=".3"/>
<circle cx="135.6" cy="110.4" r=".3"/>
<circle cx="152.9" cy="103.8" r=".3"/>
<circle cx="138.6" cy="109.8" r=".3"/>
<circle cx="149.8" cy="89.2" r=".3"/>
<circle cx="133.2" cy="109.2" r=".3"/>
<circle cx="144.6" cy="111.6" r=".3"/>
<circle cx="135.6" cy="108" r=".3"/>
<circle cx="157.6" cy="86.2" r=".3"/>
<circle cx="154.6" cy="86.2" r=".3"/>
<circle cx="149.2" cy="86.2" r=".3"/>
<circle cx="154.1" cy="104.4" r=".3"/>
<circle cx="126.6" cy="106.8" r=".3"/>
<circle cx="131.8" cy="85" r=".3"/>
<circle cx="134.2" cy="89.2" r=".3"/>
<circle cx="130" cy="89.8" r=".3"/>
<circle cx="148.2" cy="111.6" r=".3"/>
<circle cx="139.8" cy="107.4" r=".3"/>
<circle cx="147.6" cy="111.6" r=".3"/>
<circle cx="136.8" cy="111.6" r=".3"/>
<circle cx="136.8" cy="110.4" r=".3"/>
<circle cx="158.4" cy="108" r=".3"/>
<circle cx="145" cy="85.6" r=".3"/>
<circle cx="160.6" cy="85.6" r=".3"/>
<circle cx="152.3" cy="104.4" r=".3"/>
<circle cx="134.8" cy="88.6" r=".3"/>
<circle cx="156.6" cy="107.4" r=".3"/>
<circle cx="156.6" cy="108" r=".3"/>
<circle cx="132.6" cy="110.4" r=".3"/>
<circle cx="160.2" cy="108" r=".3"/>
<circle cx="148.6" cy="86.8" r=".3"/>
<circle cx="158.2" cy="85" r=".3"/>
<circle cx="132.6" cy="111.6" r=".3"/>
<circle cx="153.6" cy="107.4" r=".3"/>
<circle cx="153" cy="109.2" r=".3"/>
<circle cx="160.2" cy="108.6" r=".3"/>
<circle cx="140.2" cy="88" r=".3"/>
<circle cx="135.4" cy="88.6" r=".3"/>
<circle cx="149.2" cy="85.6" r=".3"/>
<circle cx="153.4" cy="85.6" r=".3"/>
<circle cx="142" cy="89.2" r=".3"/>
<circle cx="141" cy="109.8" r=".3"/>
<circle cx="145" cy="89.2" r=".3"/>
<circle cx="140.4" cy="110.4" r=".3"/>
<circle cx="148" cy="88.6" r=".3"/>
<circle cx="151.6" cy="87.4" r=".3"/>
<circle cx="166.4" cy="111" r=".3"/>
<circle cx="138" cy="108.6" r=".3"/>
<circle cx="125.8" cy="91" r=".3"/>
<circle cx="136.2" cy="108.6" r=".3"/>
<circle cx="144.4" cy="87.4" r=".3"/>
<circle cx="137.2" cy="88.6" r=".3"/>
<circle cx="138.4" cy="86.8" r=".3"/>
<circle cx="143.8" cy="88" r=".3"/>
<circle cx="157.2" cy="111.6" r=".3"/>
<circle cx="133.8" cy="108" r=".3"/>
<circle cx="138" cy="110.4" r=".3"/>
<circle cx="147.4" cy="88.6" r=".3"/>
<circle cx="143.2" cy="85.6" r=".3"/>
<circle cx="152.3" cy="105" r=".3"/>
<circle cx="135.6" cy="108.6" r=".3"/>
<circle cx="137.4" cy="108" r=".3"/>
<circle cx="140.4" cy="106.8" r=".3"/>
<circle cx="133" cy="87.4" r=".3"/>
<circle cx="147" cy="111" r=".3"/>
<circle cx="138.6" cy="106.8" r=".3"/>
<circle cx="146.8" cy="86.8" r=".3"/>
<circle cx="131.4" cy="110.4" r=".3"/>
<circle cx="159.6" cy="111.6" r=".3"/>
<circle cx="137.8" cy="85.6" r=".3"/>
<circle cx="137.4" cy="110.4" r=".3"/>
<circle cx="139.8" cy="110.4" r=".3"/>
<circle cx="155.1" cy="99.4" r=".3"/>
<circle cx="135.4" cy="86.2" r=".3"/>
<circle cx="134.8" cy="88" r=".3"/>
<circle cx="132.6" cy="106.8" r=".3"/>
<circle cx="138" cy="106.2" r=".3"/>
<circle cx="133.6" cy="89.2" r=".3"/>
<circle cx="154.6" cy="91.2" r=".3"/>
<circle cx="135.4" cy="89.8" r=".3"/>
<circle cx="136" cy="91" r=".3"/>
<circle cx="157.6" cy="87.4" r=".3"/>
<circle cx="158.2" cy="88.6" r=".3"/>
<circle cx="144.6" cy="110.4" r=".3"/>
<circle cx="148.8" cy="109.2" r=".3"/>
<circle cx="153" cy="111" r=".3"/>
<circle cx="154.8" cy="111" r=".3"/>
<circle cx="133.8" cy="111" r=".3"/>
<circle cx="147.6" cy="109.2" r=".3"/>
<circle cx="152.4" cy="111.6" r=".3"/>
<circle cx="141.6" cy="108" r=".3"/>
<circle cx="135.4" cy="87.4" r=".3"/>
<circle cx="139.6" cy="88.6" r=".3"/>
<circle cx="160.8" cy="108.6" r=".3"/>
<circle cx="156.4" cy="89.2" r=".3"/>
<circle cx="154" cy="91.2" r=".3"/>
<circle cx="139.8" cy="108" r=".3"/>
<circle cx="139" cy="85.6" r=".3"/>
<circle cx="155.4" cy="109.2" r=".3"/>
<circle cx="132.6" cy="111" r=".3"/>
<circle cx="140.4" cy="108" r=".3"/>
<circle cx="133.8" cy="111.6" r=".3"/>
<circle cx="147.4" cy="89.2" r=".3"/>
<circle cx="130" cy="90.4" r=".3"/>
<circle cx="159.4" cy="86.2" r=".3"/>
<circle cx="167" cy="107.4" r=".3"/>
<circle cx="138.4" cy="88.6" r=".3"/>
<circle cx="134.8" cy="87.4" r=".3"/>
<circle cx="140.8" cy="88.6" r=".3"/>
<circle cx="134.4" cy="108" r=".3"/>
<circle cx="152.2" cy="86.8" r=".3"/>
<circle cx="160" cy="88" r=".3"/>
<circle cx="152.8" cy="88.6" r=".3"/>
<circle cx="158.8" cy="86.8" r=".3"/>
<circle cx="125.8" cy="90.4" r=".3"/>
<circle cx="146.2" cy="88.6" r=".3"/>
<circle cx="142.8" cy="111.6" r=".3"/>
<circle cx="151.8" cy="109.8" r=".3"/>
<circle cx="145.6" cy="85.6" r=".3"/>
<circle cx="143.8" cy="89.2" r=".3"/>
<circle cx="146.2" cy="86.8" r=".3"/>
<circle cx="133" cy="86.8" r=".3"/>
<circle cx="135.4" cy="88" r=".3"/>
<circle cx="155.1" cy="98.8" r=".3"/>
<circle cx="160.2" cy="109.8" r=".3"/>
<circle cx="142.8" cy="111" r=".3"/>
<circle cx="166.7" cy="88" r=".3"/>
<circle cx="134.2" cy="88.6" r=".3"/>
<circle cx="148.6" cy="87.4" r=".3"/>
<circle cx="159.6" cy="108.6" r=".3"/>
<circle cx="155.2" cy="89.2" r=".3"/>
<circle cx="160" cy="85.6" r=".3"/>
<circle cx="150.4" cy="89.2" r=".3"/>
<circle cx="139.8" cy="106.8" r=".3"/>
<circle cx="149.2" cy="87.4" r=".3"/>
<circle cx="137.8" cy="86.8" r=".3"/>
<circle cx="155.2" cy="86.8" r=".3"/>
<circle cx="131.8" cy="88.6" r=".3"/>
<circle cx="157" cy="85.6" r=".3"/>
<circle cx="143.2" cy="86.8" r=".3"/>
<circle cx="160" cy="86.8" r=".3"/>
<circle cx="149.4" cy="111" r=".3"/>
<circle cx="141" cy="108.6" r=".3"/>
<circle cx="145.2" cy="109.2" r=".3"/>
<circle cx="149.8" cy="87.4" r=".3"/>
<circle cx="144.6" cy="109.8" r=".3"/>
<circle cx="149.4" cy="109.2" r=".3"/>
<circle cx="159" cy="108" r=".3"/>
<circle cx="145.2" cy="110.4" r=".3"/>
<circle cx="151.8" cy="110.4" r=".3"/>
<circle cx="153.6" cy="108.6" r=".3"/>
<circle cx="142" cy="88.6" r=".3"/>
<circle cx="152.2" cy="88" r=".3"/>
<circle cx="142" cy="86.2" r=".3"/>
<circle cx="126" cy="108" r=".3"/>
<circle cx="155.8" cy="88" r=".3"/>
<circle cx="154.6" cy="88" r=".3"/>
<circle cx="154.1" cy="103.2" r=".3"/>
<circle cx="139.8" cy="111.6" r=".3"/>
<circle cx="140.8" cy="87.4" r=".3"/>
<circle cx="166.7" cy="85.6" r=".3"/>
<circle cx="140.2" cy="86.2" r=".3"/>
<circle cx="160.2" cy="111" r=".3"/>
<circle cx="149.2" cy="89.2" r=".3"/>
<circle cx="136" cy="85.6" r=".3"/>
<circle cx="132.4" cy="85.6" r=".3"/>
<circle cx="145.6" cy="88" r=".3"/>
<circle cx="147" cy="111.6" r=".3"/>
<circle cx="150" cy="110.4" r=".3"/>
<circle cx="126" cy="111.6" r=".3"/>
<circle cx="141.6" cy="110.4" r=".3"/>
<circle cx="136" cy="90.4" r=".3"/>
<circle cx="154" cy="87.4" r=".3"/>
<circle cx="154.6" cy="85.6" r=".3"/>
<circle cx="135" cy="111" r=".3"/>
<circle cx="155.4" cy="107.4" r=".3"/>
<circle cx="141.6" cy="109.2" r=".3"/>
<circle cx="144" cy="111.6" r=".3"/>
<circle cx="158.8" cy="88.6" r=".3"/>
<circle cx="144.4" cy="86.8" r=".3"/>
<circle cx="147.4" cy="85.6" r=".3"/>
<circle cx="141" cy="108" r=".3"/>
<circle cx="136.2" cy="111.6" r=".3"/>
<circle cx="154.2" cy="109.2" r=".3"/>
<circle cx="129.4" cy="91" r=".3"/>
<circle cx="131.4" cy="106.8" r=".3"/>
<circle cx="143.8" cy="85.6" r=".3"/>
<circle cx="137.4" cy="111.6" r=".3"/>
<circle cx="161.2" cy="89.2" r=".3"/>
<circle cx="154.2" cy="111.6" r=".3"/>
<circle cx="151.8" cy="92.4" r=".3"/>
<circle cx="139.2" cy="108" r=".3"/>
<circle cx="140.4" cy="111.6" r=".3"/>
<circle cx="133" cy="86.2" r=".3"/>
<circle cx="158.4" cy="111" r=".3"/>
<circle cx="159.6" cy="109.8" r=".3"/>
<circle cx="142.9" cy="104.2" r=".3"/>
<circle cx="146.3" cy="100.2" r=".3"/>
<circle cx="149.8" cy="103.4" r=".3"/>
<circle cx="127.1" cy="101.4" r=".3"/>
<circle cx="127.1" cy="100.6" r=".3"/>
<circle cx="126.9" cy="97" r=".3"/>
<circle cx="126.9" cy="96.1" r=".3"/>
<circle cx="164.2" cy="102.6" r=".3"/>
<circle cx="148.8" cy="90.4" r=".3"/>
<circle cx="164.2" cy="100.1" r=".3"/>
<circle cx="146.2" cy="92.7" r=".3"/>
<circle cx="146.6" cy="91.8" r=".3"/>
<circle cx="164.2" cy="98.2" r=".3"/>
<circle cx="164.2" cy="101.2" r=".3"/>
<circle cx="143.8" cy="90.4" r=".3"/>
<circle cx="154.1" cy="96" r=".3"/>
<circle cx="153.6" cy="98.8" r=".3"/>
<circle cx="142" cy="92.3" r=".3"/>
<circle cx="147.6" cy="96" r=".3"/>
<circle cx="148.4" cy="96" r=".3"/>
<circle cx="142.3" cy="91.6" r=".3"/>
<circle cx="132.5" cy="95.7" r=".3"/>
<circle cx="132.5" cy="97.5" r=".3"/>
<circle cx="130.7" cy="101.5" r=".3"/>
<circle cx="131" cy="100.7" r=".3"/>
<circle cx="160.2" cy="102.8" r=".3"/>
<circle cx="160.2" cy="101.6" r=".3"/>
<circle cx="160.3" cy="100.1" r=".3"/>
<circle cx="160.4" cy="98.2" r=".3"/>
<circle cx="127.9" cy="99.2" r=".3"/>
</g>
<path d="M143.2 91.3l.5 .5v.3l2.8 2.8h2.1l1 1h2.7l.3 .3v1.5l-.3 .3h-.7l-.3 .4v.6l-.3-.2h-1.6M149.4 99.8v.9l.4 .4h1l.5-.5" fill="none" stroke="#c83434" stroke-width=".3"/>
<g fill="none" stroke="#c83434" stroke-width=".21">
<path d="M126.9 96.1l.2 .2h.3M127.4 96.7h.1M127.4 96.7l1.3 1.4h.9l.2 .2h.4l.2-.2h6.5l.6-.6M127.4 96.3h.1M127.4 96.7h-.3l-.2 .3M132.5 97.5h2M132.5 95.7l.3 .2h1.7M137.2 96.5h3.7M137.5 95.6l-.6-.6h-6.5l-.2-.3h-.4l-.2 .3h-.9l-1.3 1.3M137.5 97.5l.4-.4h1.6l1.5 1.5h1.7l.1-1.8 .2-.2 .1 .2 .1 1.8h.2l.8-.8h.8M137.5 95.6l.4 .4h1.6l1.4-1.5h2.2l2.9 2.8-.1 1h-.9M139.5 96.5h.1"/>
<path d="M141.8 95.3v2.5M141.8 99.8v1l.2 .2-.2 .2v1M142 92.3l3.7 3.7h1.9l.8 .8v1.2l.2 .3h2.1l.9-.9h.4M142.3 91.6h.2l3.8 3.8h1.5l1.5 1.3h2.5l.2-.2M143 91.3h.2M143.8 90.4l.6 .6h4.8l.5-.5h16.3l.7 .7v7.7l-2.3 2.3h-.2M145 99.8v2.8l-.4 .4h-3.7l-1.4-1.4h-1.6l-.4 .4v.3l-.3 .3h-6.2l-1.2-1.2h-1.1l-.3 .4-.4-.4h-.9M145 99.3h-1.5l-.2 1.5-.2-.1v-1.4h-.6l-.3-.3h-1.3l-1.4 1.4h-1.6l-.4-.3-.2-.5h-6.5l-1 1h-1.1l-.3-.5-.2 .1-.1 .4h-1M145 98.8h2.2v5.6l-1.3 1.3-.8-.8h-13l-.4-.4h-.5M146.2 92.7l.2 .2h10.6l1.1-1.1h.7l.9-.9h5.7l.7 .7v6.9l-1.6 1.6h-.3M146.6 91.8h-.3l-.7 .7v.5l.4 .3h11.1l1.1-1.1h1.2l.8-.8h4.9l.3 .3v5.8l-.7 .7h-.4M148.8 90.4l.3-.3h17.6l.7 .7v8.2l-3.2 3.2v.4"/>
<path d="M149.4 99.3h-.8l-.2 .1v.6l-.2 .2v5l-.9 .9h-3.7M151.4 96.7l-1.1 1.1h-.9M155 95.1l-.9 .9M155.1 96.7h-.5l-1 1v1.1M155.7 95.1l2.5 .1h-1.2M155.8 96.7h2.4M158.2 99.7h1.7l.4 .4M158.2 98.2h2.2M160.4 92l.6 .6h1.9l-1.1 1.1h-8l-.6 .6v3.5l-.7 .6h-.2v2.2h.8l4.7 4.7h5.1M130.7 101.5h3.4l.4 .4M134.5 100.4l-.5 .5h-2.9l-.1-.2M136.7 101h4.3"/>
<path d="M137.7 104.4l-1.2-1.2h-5.4l-1.3 1.3M150.4 106.1l1.4 1.5h.5M152.3 100.4v.3M158.2 101.2h1.6l.5 .4M158.2 102.7l2 .1"/>
</g>
<path d="M134.5 99h-6.3l-.3 .2M146.3 100.2v1.8l-2.2 2.2h-1.2M151.3 103.3l-1.5 .1M151.3 100.6v4.2l1.5 1.5v1.7l-.2 .2h-.3" fill="none" stroke="#c83434" stroke-width=".4"/>
<g fill="#c83434">
<path d="M125.2 84.5h42.4l-.1 5.5-.7-.5-18 .1a1.1 1.1 0 0 0-.9 .8h-3.3a.88 .88 0 0 0-.9-.8 .88 .88 0 0 0-.8 .9l-.6 .3a1 1 0 0 0-.9 1 .83 .83 0 0 0 .6 1.3l.6 .6-.1 .2h-1.6l-.6 .4h-.4a.75 .75 0 0 0-.7 1l-.6 .1-.3-.6h-.8l-.5-.4h-4.7l-.1-.9h-4.8l.1 .9 .5 .4-.6 .7a.88 .88 0 0 0-1.1 0 .88 .88 0 0 0-.2 1.1 .88 .88 0 0 0 .3 1 .88 .88 0 0 0 1.1 0l.5 .6-.2 .2a.91 .91 0 0 0-.6 1.3 .93 .93 0 0 0-.8 1.4 .88 .88 0 0 0 .3 1 .88 .88 0 0 0 1.1 0 .89 .89 0 0 0 1.3-.1h.5l.9 .9-.1 .2h-.3v1.1h2.1l-.1-.9 .1-.2h5.1l.6-.4a.66 .66 0 0 0 .7-.6h.6l.1 .7 .4 .4h.7l.5 .4h1.3a1.36 1.36 0 0 0 .2 1.4l-.3 .5v1.3l.3 .4h2.4l.5-.5h2.1l1.3-1.1 .2 1.4 .3 .2h1.4l1 .9a.71 .71 0 0 0 1 .8l.4-.1 .5-.6v-2h7l.1 .4 .4 .1h3.8l.4-.1 .1-.4v-.7h-2.1v1.2h-.6v-1.2h-2.1v.7h-7l-.2-.4-1.3-1.5h8.5v.7h4.8v-.7l-.4-.4h-1.7v1.1h-.6v-1.1h-1.7l-.4 .4h-8.5v-2.4l.6-.2a.71 .71 0 0 0 .6-.9h-.6v.9h-.5v-2.9h.5v1.6h.6l-.1-.6 .2-.3a.81 .81 0 0 0 .9-.2 .81 .81 0 0 0 0-1v-.3l.4-.4h1.6l.2 1.3-.2 4.2 .2 .4 .3 .1h3.1a.92 .92 0 0 0 .9-.2 .92 .92 0 0 0 .3-1l-.2-.2a.95 .95 0 0 0-.2-1.4 .9 .9 0 0 0 .5-.9 .9 .9 0 0 0-.8-.7v-.2a.85 .85 0 0 0 .9-.9 .85 .85 0 0 0-1.1-.8v-2.6l-.3-.4-3.4 .1-.4-.2-1.3 .1-.3 .2-.1 .5-.7 .4-.4 .5-.7-.6-2.4-.1-1.3-.9-2-.1-.2-.2 10.6-.1 .5-.4h2.8l.4 .5h1.7v-1.2h-2.1v.7h-2.8l.8-.7h1.1l.7-.7 .2 .2h2.5l.2 .2v1.5l1.6 .1v3.1l-.2 .2a.83 .83 0 0 0-1.2 .7 .83 .83 0 0 0 1 .9l.2 .1-.2 .2a.91 .91 0 0 0-.9 .4 .91 .91 0 0 0 0 1 1.24 1.24 0 0 0 .1 1.3 .84 .84 0 0 0 .5 1.4 .84 .84 0 0 0 .9-1.2l2.4-2.3h.2l-.1 12.3h-42.2l-.1-2.8h2a1.35 1.35 0 0 0 1.3 1.5 1.35 1.35 0 0 0 1.5-1.4h32.4v.2a1.35 1.35 0 0 0 2.1 1.1 1.35 1.35 0 0 0 0-2.4 1.35 1.35 0 0 0-2.1 1.1l-32.4-.1a1.35 1.35 0 0 0-1.4-1.3 1.35 1.35 0 0 0-1.4 1.3h-2v-4h2.2l.1 .4 .4 .1h3.8l.4-.1 .1-.4v-.6h-2.1v1.1h-.6v-1.1h-2.1v.6h-2.2v-1.8h2.2v.6h2.1v-1.1h-1.7l-.4 .5h-2.2v-11.2h2.2v.7h4.8l-.1-.9-.4-.3h-1.6v1.2h-.6v-1.2h-1.7l-.4 .5h-2.2v-5.3h2.3a1.35 1.35 0 0 0 1.4 1.5 1.35 1.35 0 0 0 1.3-1.6h32.4v.2a1.35 1.35 0 0 0 2.1 1.1 1.35 1.35 0 0 0 0-2.4 1.35 1.35 0 0 0-2.1 1.1h-32.4v-.1a1.35 1.35 0 0 0-1.4-1.1 1.35 1.35 0 0 0-1.3 1.3h-2.3z"/>
<path d="M146.3 96.6h.8l.7 .5-.3 .2 .1 7.6-.6 .6h-1.7a.63 .63 0 0 0-.8-.5l-.1-.2 2.5-2.6 .2-2-.2-1.2h-.7l-.1-.2 .4-.3h.4v-1.2l-.4-.1z"/>
<path d="M136.5 100.8h.9l.2 .2-.2 .2-.9 .1-.2-.1z"/>
<path d="M139.8 100.9l.2-.1h1.1l.1 .3-.1 .1h-1.1z"/>
<path d="M136.5 96.3h.9l.2 .2-.1 .2-1 .1-.2-.1z"/>
<path d="M139.8 96.4l.2-.1h.9l.2 .3-.2 .2h-.9z"/>
<path d="M147.5 91.6h1.8l.7-.5h7.6l.1 .1-1 1.1h-9.3l-.1-.1z"/>
</g>
</svg>
